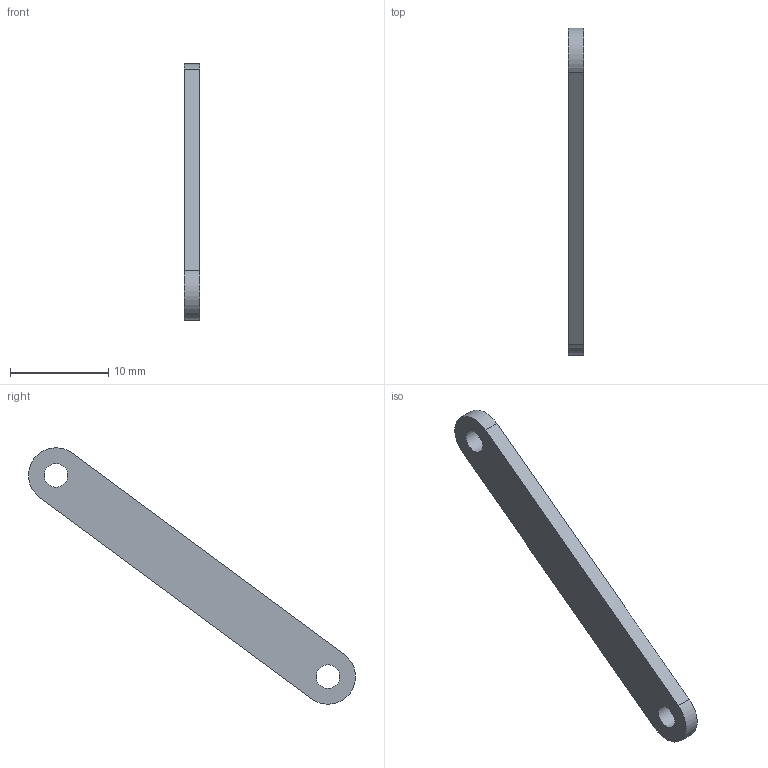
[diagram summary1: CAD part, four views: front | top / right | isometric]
STEP (ISO 10303-21) file: header records copied from the file, then geometry measured from it (millimetres).
FILE_DESCRIPTION(('Open CASCADE Model'),'2;1');
FILE_NAME('Open CASCADE Shape Model','2026-10-30T16:43:28',('Author'),( 'Open CASCADE'),'Open CASCADE STEP processor 8.0','Open CASCADE 8.0' ,'Unknown');
FILE_SCHEMA(('AP242_MANAGED_MODEL_BASED_3D_ENGINEERING_MIM_LF {1 0 10303 442 1 1 4 }' ));
Length unit declared in the file: millimetre
Products named in the file (1): Open CASCADE STEP translator 8.0 5
Bounding box: 1.6 x 33.29 x 26.09 mm (x, y, z)
Volume: 289 mm3; surface area: 616.9 mm2
Topology: 1 solids, 1 shells, 13 faces, 30 edges, 20 vertices
Faces by surface type: plane 9, cylinder 4
Full cylindrical faces by diameter (mm): 2.4 x2
Entity records: 776 total; most frequent: CARTESIAN_POINT 146, DIRECTION 114, LINE 64, VECTOR 64, ORIENTED_EDGE 60, PCURVE 60, DEFINITIONAL_REPRESENTATION 60, EDGE_CURVE 30
